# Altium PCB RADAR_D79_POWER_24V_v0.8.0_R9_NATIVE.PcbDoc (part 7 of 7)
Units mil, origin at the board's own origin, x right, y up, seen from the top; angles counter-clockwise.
Board outline 3110.24 x 3110.24 mil, 8 copper layers (Top Layer, GND1, SIG1, PWR1, PWR2, SIG2, GND2, Bottom Layer), stack 55.2 mil thick; 304 components, 269 nets, 1408 pads, 1366 vias.

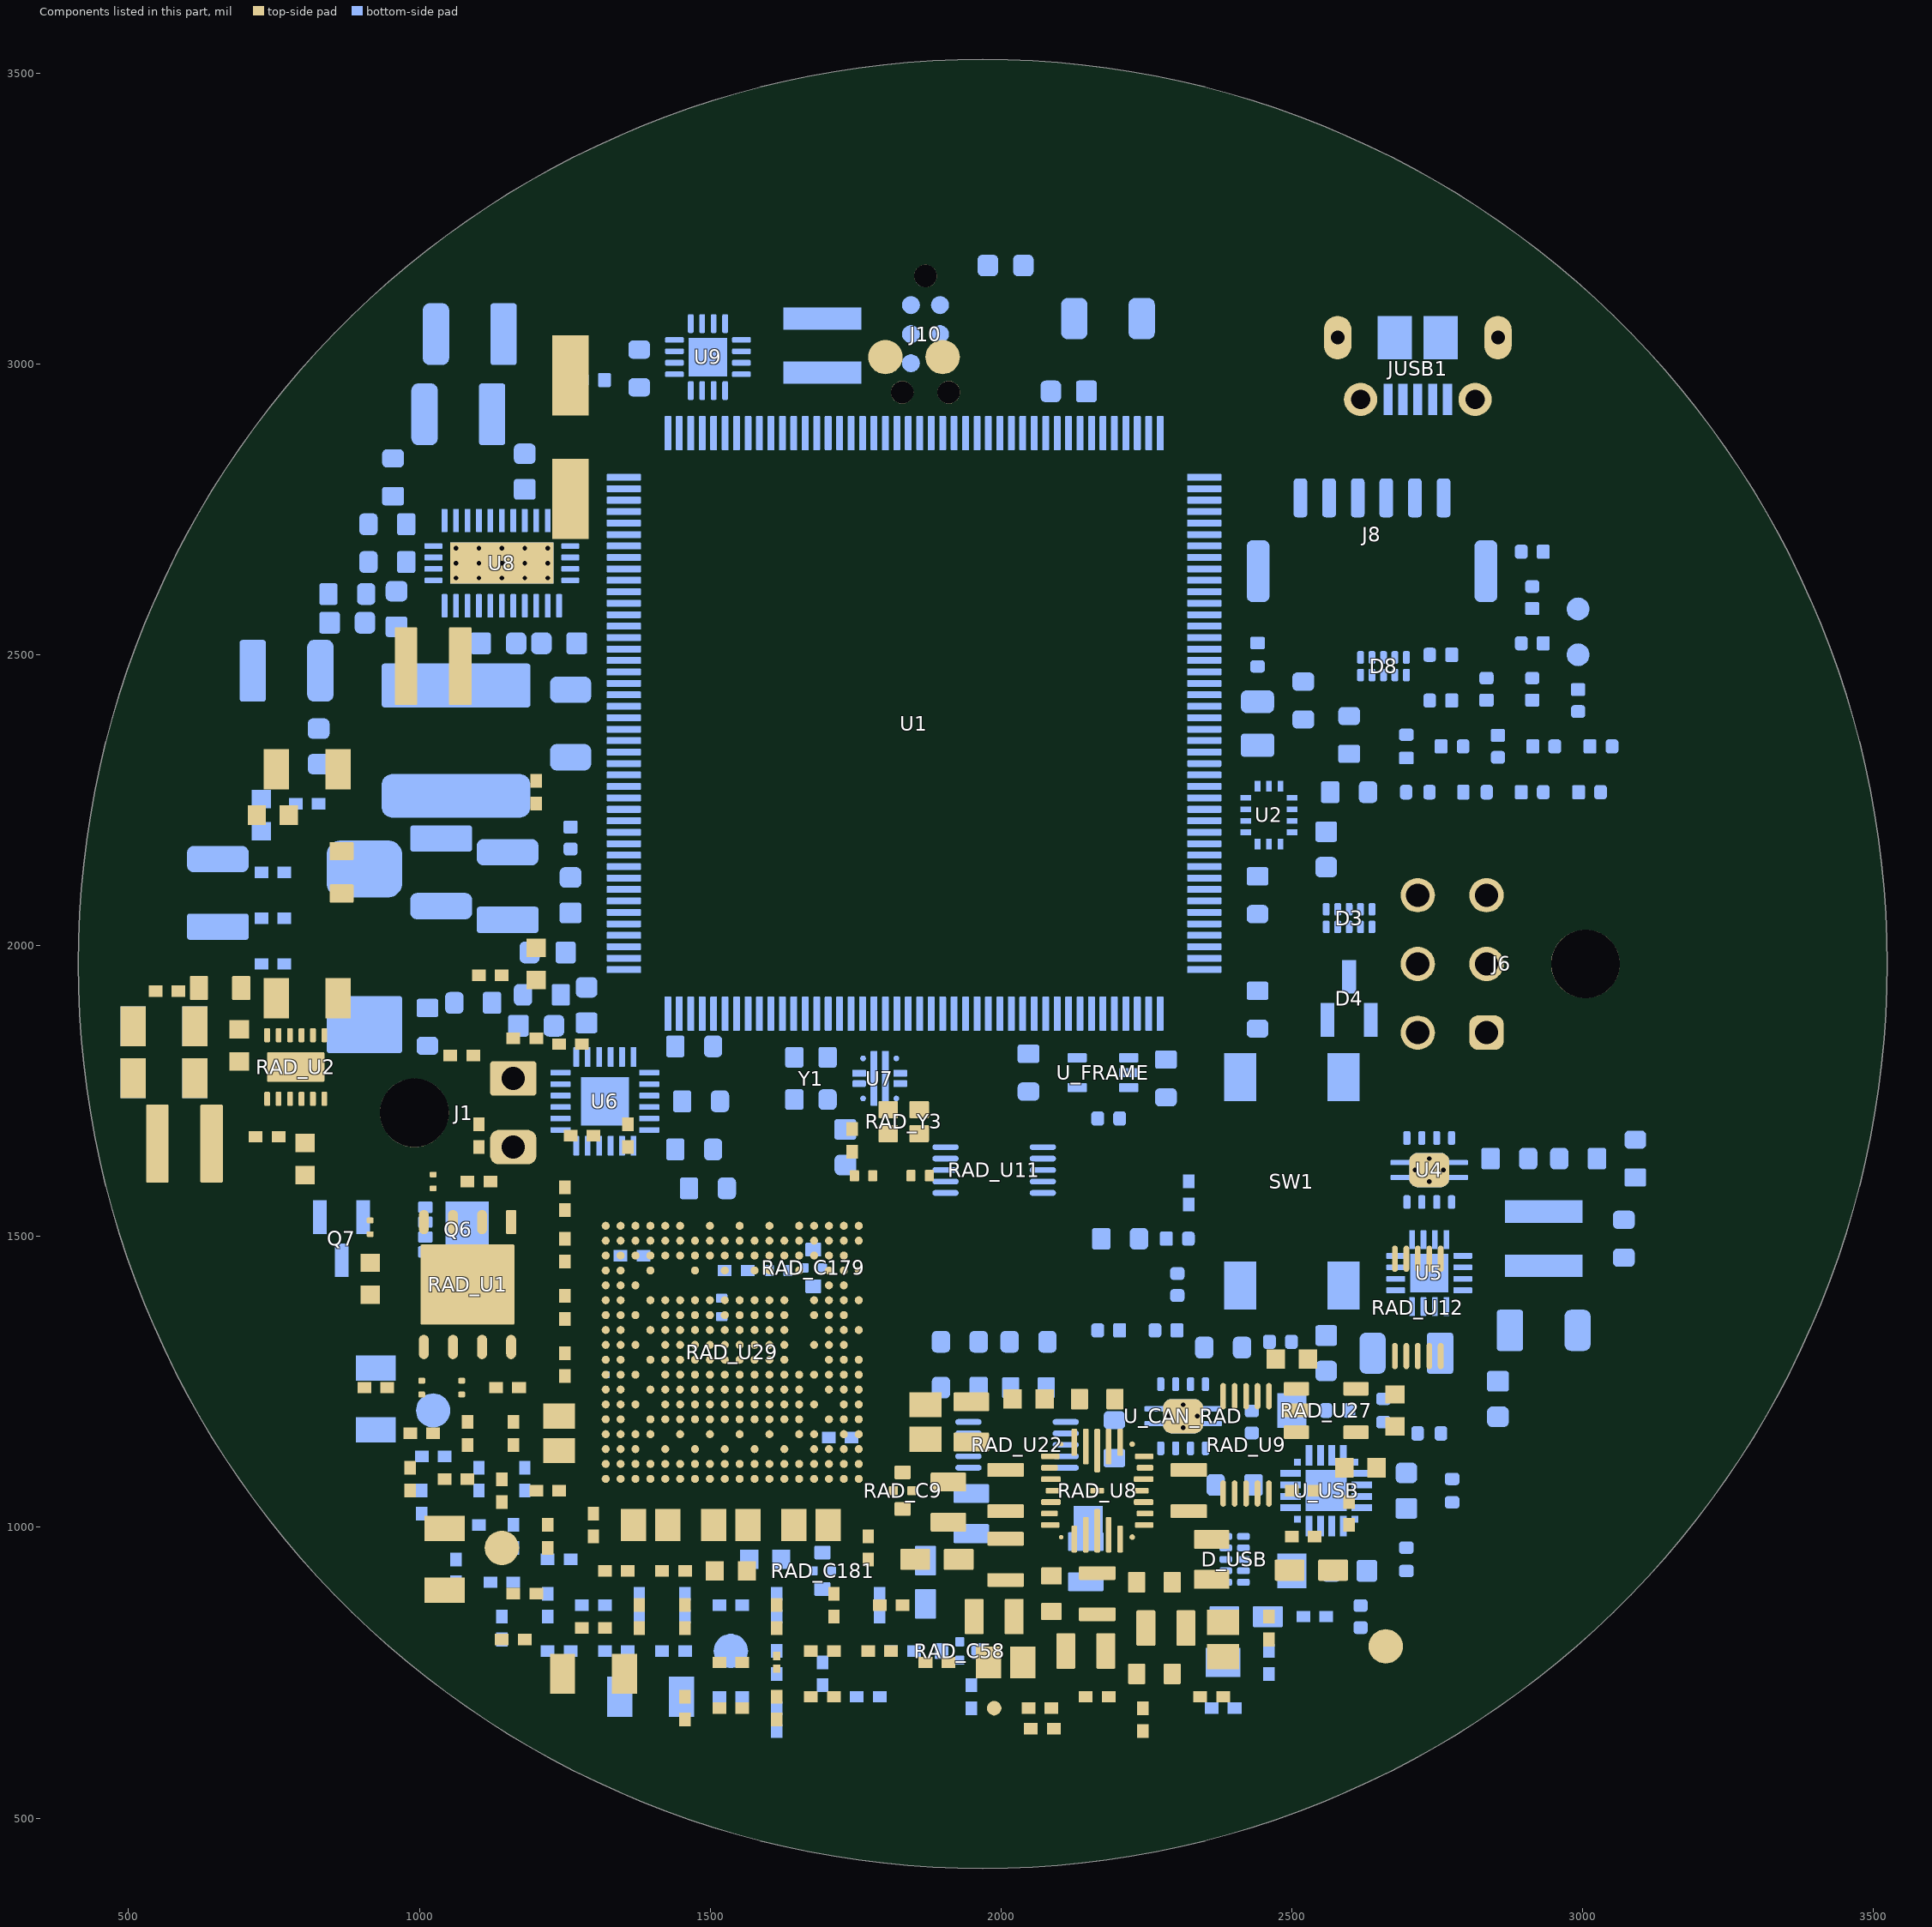
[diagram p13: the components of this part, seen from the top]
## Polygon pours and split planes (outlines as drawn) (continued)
GND on Bottom Layer "GND_BOTTOM_RETURN" (solid, remove dead copper, pour order 5): 3474.41,1968.5 3472.98,2034.19 3468.68,2099.75 3461.53,2165.06 3451.53,2230 3438.71,2294.44 3423.1,2358.26 3404.71,2421.34 3383.59,2483.55 3359.78,2544.79 3333.32,2604.93 3304.26,2663.85 3272.66,2721.46 3238.57,2777.63 3202.07,2832.26 3163.22,2885.24 3122.09,2936.48 3078.77,2985.88 3033.34,3033.34 2985.88,3078.77 2936.48,3122.09 2885.24,3163.22 2832.26,3202.07 2777.63,3238.57 2721.46,3272.66 2663.85,3304.26 2604.93,3333.32 2544.79,3359.78 2483.55,3383.59 2421.34,3404.71 2358.26,3423.1 2294.44,3438.71 2230,3451.53 2165.06,3461.53 2099.75,3468.68 2034.19,3472.98 1968.5,3474.41 1902.82,3472.98 1837.26,3468.68 1771.94,3461.53 1707.01,3451.53 1642.57,3438.71 1578.75,3423.1 1515.67,3404.71 1453.45,3383.59 1392.22,3359.78 1332.08,3333.32 1273.15,3304.26 1215.55,3272.66 1159.38,3238.57 1104.75,3202.07 1051.77,3163.22 1000.53,3122.09 951.13,3078.77 903.67,3033.34 858.23,2985.88 814.91,2936.48 773.79,2885.24 734.94,2832.26 698.44,2777.63 664.35,2721.46 632.75,2663.85 603.69,2604.93 577.23,2544.79 553.42,2483.55 532.3,2421.34 513.91,2358.26 498.29,2294.44 485.48,2230 475.48,2165.06 468.33,2099.75 464.03,2034.19 462.6,1968.5 464.03,1902.82 468.33,1837.26 475.48,1771.94 485.48,1707.01 498.29,1642.57 513.91,1578.75 532.3,1515.67 553.42,1453.45 577.23,1392.22 603.69,1332.08 632.75,1273.15 664.35,1215.55 698.44,1159.38 734.94,1104.75 773.79,1051.77 814.91,1000.53 858.23,951.13 903.67,903.67 951.13,858.23 1000.53,814.91 1051.77,773.79 1104.75,734.94 1159.38,698.44 1215.55,664.35 1273.15,632.75 1332.08,603.69 1392.22,577.23 1453.45,553.42 1515.67,532.3 1578.75,513.91 1642.57,498.29 1707.01,485.48 1771.94,475.48 1837.26,468.33 1902.82,464.03 1968.5,462.6 2034.19,464.03 2099.75,468.33 2165.06,475.48 2230,485.48 2294.44,498.29 2358.26,513.91 2421.34,532.3 2483.55,553.42 2544.79,577.23 2604.93,603.69 2663.85,632.75 2721.46,664.35 2777.63,698.44 2832.26,734.94 2885.24,773.79 2936.48,814.91 2985.88,858.23 3033.34,903.67 3078.77,951.13 3122.09,1000.53 3163.22,1051.77 3202.07,1104.75 3238.57,1159.38 3272.66,1215.55 3304.26,1273.15 3333.32,1332.08 3359.78,1392.22 3383.59,1453.45 3404.71,1515.67 3423.1,1578.75 3438.71,1642.57 3451.53,1707.01 3461.53,1771.94 3468.68,1837.26 3472.98,1902.82
TI_REGOUT_3V3 on PWR2 "REGOUT_3V3_WINDOW_8" (solid, pour order 8): 1479.33,1128.16 1484.49,1125.52 1489.88,1123.39 1495.45,1121.81 1501.16,1120.77 1506.93,1120.31 1512.73,1120.41 1518.48,1121.07 1524.15,1122.3 1529.66,1124.08 1534.98,1126.39 1540.04,1129.21 1544.81,1132.51 1549.22,1136.26 1553.25,1140.43 1556.85,1144.97 1559.99,1149.84 1562.63,1155 1564.75,1160.39 1566.34,1165.97 1567.37,1171.67 1567.84,1177.44 1567.74,1183.24 1567.08,1189 1565.85,1194.66 1564.07,1200.18 1561.76,1205.49 1558.94,1210.56 1555.64,1215.32 1551.89,1219.73 1547.72,1223.76 1543.18,1227.36 1538.31,1230.5 592.48,1775.58 587.32,1778.22 581.93,1780.35 576.36,1781.93 570.65,1782.97 564.88,1783.43 559.08,1783.34 553.33,1782.67 547.66,1781.44 542.15,1779.66 536.83,1777.35 531.77,1774.53 527,1771.23 522.59,1767.48 518.56,1763.31 514.96,1758.77 511.83,1753.9 509.18,1748.74 507.06,1743.35 505.47,1737.77 504.44,1732.07 503.97,1726.3 504.07,1720.5 504.73,1714.74 505.96,1709.08 507.74,1703.56 510.05,1698.25 512.87,1693.18 516.17,1688.42 519.92,1684.01 524.09,1679.98 528.63,1676.38 533.5,1673.24
TI_REGOUT_3V3 on PWR2 "REGOUT_3V3_WINDOW_9" (solid, pour order 9): 1746.1,974.42 1751.26,971.78 1756.65,969.65 1762.23,968.07 1767.93,967.03 1773.7,966.57 1779.5,966.66 1785.26,967.33 1790.92,968.56 1796.44,970.34 1801.75,972.65 1806.82,975.47 1811.58,978.77 1815.99,982.52 1820.02,986.69 1823.62,991.23 1826.76,996.1 1829.4,1001.26 1831.53,1006.65 1833.11,1012.23 1834.15,1017.93 1834.62,1023.7 1834.52,1029.5 1833.85,1035.26 1832.62,1040.92 1830.84,1046.44 1828.53,1051.75 1825.72,1056.82 1822.41,1061.58 1818.66,1065.99 1814.49,1070.02 1809.95,1073.62 1805.08,1076.76 1678.97,1149.43 1673.81,1152.08 1668.42,1154.2 1662.85,1155.79 1657.14,1156.82 1651.37,1157.29 1645.57,1157.19 1639.81,1156.53 1634.15,1155.3 1628.63,1153.52 1623.32,1151.21 1618.26,1148.39 1613.49,1145.09 1609.08,1141.34 1605.05,1137.17 1601.45,1132.63 1598.31,1127.76 1595.67,1122.6 1593.54,1117.21 1591.96,1111.63 1590.92,1105.93 1590.46,1100.15 1590.55,1094.36 1591.22,1088.6 1592.45,1082.94 1594.23,1077.42 1596.54,1072.11 1599.36,1067.04 1602.66,1062.28 1606.41,1057.86 1610.58,1053.84 1615.12,1050.24 1619.99,1047.1
TI_REGOUT_3V3 on PWR2 "REGOUT_3V3_WINDOW_10" (solid, pour order 10): 1580.31,1178.91 1582.2,1178.48 1584.12,1178.24 1586.05,1178.19 1587.97,1178.34 1589.88,1178.66 1591.74,1179.18 1593.54,1179.87 1595.27,1180.74 1596.9,1181.77 1598.42,1182.96 1599.83,1184.29 1601.09,1185.75 1602.2,1187.33 1603.15,1189.01 1603.94,1190.78 1604.55,1192.61 1604.97,1194.49 1605.21,1196.41 1605.26,1198.34 1605.12,1200.27 1604.79,1202.17 1604.27,1204.03 1603.58,1205.84 1602.71,1207.56 1601.68,1209.2 1600.49,1210.72 1599.16,1212.12 1597.7,1213.38 1596.12,1214.5 1594.44,1215.45 1592.68,1216.23 1590.84,1216.84 1380.7,1275.17 1378.81,1275.59 1376.9,1275.83 1374.96,1275.88 1373.04,1275.74 1371.13,1275.41 1369.27,1274.9 1367.47,1274.2 1365.74,1273.34 1364.11,1272.3 1362.59,1271.12 1361.19,1269.79 1359.92,1268.32 1358.81,1266.74 1357.86,1265.06 1357.07,1263.3 1356.47,1261.47 1356.04,1259.58 1355.8,1257.66 1355.75,1255.73 1355.89,1253.81 1356.22,1251.9 1356.74,1250.04 1357.43,1248.24 1358.3,1246.51 1359.33,1244.88 1360.52,1243.35 1361.85,1241.95 1363.31,1240.69 1364.89,1239.58 1366.57,1238.62 1368.33,1237.84 1370.17,1237.23
TI_REGOUT_3V3 on PWR2 "REGOUT_3V3_WINDOW_11" (solid, pour order 11): 1619.9,1154.71 1621.61,1153.81 1623.4,1153.08 1625.25,1152.53 1627.15,1152.16 1629.07,1151.99 1631,1152 1632.93,1152.2 1634.82,1152.59 1636.66,1153.16 1638.44,1153.91 1640.14,1154.83 1641.74,1155.91 1643.23,1157.15 1644.59,1158.52 1645.8,1160.02 1646.87,1161.63 1647.77,1163.34 1648.49,1165.13 1649.04,1166.98 1649.41,1168.88 1649.59,1170.8 1649.58,1172.74 1649.38,1174.66 1648.99,1176.55 1648.42,1178.4 1647.67,1180.18 1646.75,1181.87 1645.66,1183.47 1644.43,1184.96 1643.05,1186.32 1641.55,1187.53 1639.94,1188.6 1595.6,1214.82 1593.89,1215.72 1592.1,1216.45 1590.25,1217 1588.35,1217.36 1586.43,1217.54 1584.5,1217.53 1582.57,1217.33 1580.68,1216.94 1578.84,1216.37 1577.06,1215.62 1575.36,1214.7 1573.76,1213.61 1572.27,1212.38 1570.91,1211.01 1569.7,1209.51 1568.63,1207.89 1567.73,1206.18 1567.01,1204.39 1566.46,1202.54 1566.09,1200.65 1565.91,1198.72 1565.92,1196.79 1566.12,1194.87 1566.51,1192.98 1567.08,1191.13 1567.83,1189.35 1568.75,1187.65 1569.84,1186.05 1571.07,1184.57 1572.45,1183.21 1573.95,1181.99 1575.56,1180.93
TI_REGOUT_3V3 on PWR2 "REGOUT_3V3_WINDOW_12" (solid, pour order 12): 1761.65,1011.69 1763.08,1010.39 1764.63,1009.24 1766.29,1008.24 1768.03,1007.41 1769.85,1006.76 1771.72,1006.29 1773.63,1006 1775.56,1005.91 1777.49,1006 1779.4,1006.28 1781.28,1006.75 1783.1,1007.39 1784.85,1008.22 1786.5,1009.21 1788.06,1010.36 1789.49,1011.65 1790.79,1013.08 1791.94,1014.63 1792.94,1016.29 1793.77,1018.03 1794.42,1019.85 1794.89,1021.72 1795.18,1023.63 1795.28,1025.56 1795.18,1027.49 1794.9,1029.4 1794.44,1031.28 1793.79,1033.1 1792.96,1034.85 1791.97,1036.5 1790.82,1038.06 1789.53,1039.49 1643.86,1185.55 1642.43,1186.85 1640.88,1188.01 1639.22,1189 1637.48,1189.83 1635.66,1190.48 1633.79,1190.96 1631.88,1191.24 1629.95,1191.34 1628.02,1191.25 1626.11,1190.97 1624.23,1190.5 1622.41,1189.85 1620.67,1189.03 1619.01,1188.04 1617.45,1186.89 1616.02,1185.59 1614.72,1184.16 1613.57,1182.61 1612.57,1180.96 1611.74,1179.21 1611.09,1177.39 1610.62,1175.52 1610.33,1173.61 1610.24,1171.68 1610.33,1169.75 1610.61,1167.84 1611.08,1165.96 1611.72,1164.14 1612.55,1162.4 1613.54,1160.74 1614.69,1159.19 1615.98,1157.75
TI_REGOUT_3V3 on PWR2 "REGOUT_3V3_WINDOW_13" (solid, pour order 13): 1513.98,1087.64 1517.05,1085.29 1520.33,1083.26 1523.8,1081.56 1527.42,1080.2 1531.15,1079.21 1534.97,1078.59 1538.82,1078.35 1542.68,1078.48 1546.51,1078.99 1550.27,1079.88 1553.93,1081.13 1557.45,1082.73 1560.79,1084.67 1563.92,1086.93 1566.82,1089.48 1569.46,1092.31 1571.8,1095.38 1573.84,1098.66 1575.54,1102.13 1576.89,1105.75 1577.88,1109.49 1578.5,1113.3 1578.75,1117.15 1578.61,1121.02 1578.1,1124.85 1577.22,1128.61 1575.97,1132.26 1574.36,1135.78 1572.42,1139.12 1570.17,1142.25 1567.61,1145.15 1564.79,1147.79 1400.84,1286.28 1397.77,1288.62 1394.48,1290.66 1391.01,1292.36 1387.39,1293.71 1383.66,1294.7 1379.85,1295.32 1375.99,1295.57 1372.13,1295.43 1368.3,1294.92 1364.54,1294.03 1360.88,1292.78 1357.37,1291.18 1354.03,1289.24 1350.89,1286.99 1347.99,1284.43 1345.36,1281.61 1343.01,1278.54 1340.98,1275.25 1339.28,1271.78 1337.92,1268.16 1336.93,1264.43 1336.31,1260.62 1336.07,1256.76 1336.2,1252.9 1336.71,1249.07 1337.6,1245.31 1338.85,1241.65 1340.45,1238.14 1342.39,1234.79 1344.65,1231.66 1347.2,1228.76 1350.03,1226.12
TI_REGOUT_3V3 on PWR2 "REGOUT_3V3_WINDOW_14" (solid, pour order 14): 1565.21,1058.46 1568.68,1056.76 1572.3,1055.4 1576.03,1054.41 1579.84,1053.79 1583.7,1053.55 1587.56,1053.68 1591.39,1054.2 1595.15,1055.08 1598.81,1056.33 1602.32,1057.93 1605.66,1059.87 1608.8,1062.13 1611.7,1064.69 1614.33,1067.51 1616.68,1070.58 1618.71,1073.87 1620.41,1077.34 1621.76,1080.96 1622.75,1084.69 1623.37,1088.5 1623.62,1092.36 1623.48,1096.22 1622.97,1100.05 1622.08,1103.81 1620.83,1107.47 1619.23,1110.98 1617.29,1114.32 1615.03,1117.46 1612.48,1120.36 1609.65,1122.99 1606.58,1125.34 1603.3,1127.37 1558.43,1152.17 1554.96,1153.87 1551.34,1155.22 1547.6,1156.21 1543.79,1156.84 1539.93,1157.08 1536.07,1156.94 1532.24,1156.43 1528.48,1155.54 1524.83,1154.29 1521.31,1152.69 1517.97,1150.75 1514.84,1148.49 1511.94,1145.94 1509.3,1143.11 1506.96,1140.04 1504.92,1136.76 1503.22,1133.29 1501.87,1129.67 1500.88,1125.93 1500.26,1122.12 1500.02,1118.27 1500.15,1114.4 1500.66,1110.57 1501.55,1106.81 1502.8,1103.16 1504.4,1099.64 1506.34,1096.3 1508.6,1093.17 1511.15,1090.27 1513.98,1087.63 1517.05,1085.29 1520.34,1083.26
TI_REGOUT_3V3 on PWR2 "REGOUT_3V3_WINDOW_15" (solid, pour order 15): 1681.59,1048.86 1685.46,1048.87 1689.3,1049.25 1693.09,1050.01 1696.78,1051.14 1700.35,1052.62 1703.76,1054.45 1706.96,1056.6 1709.95,1059.06 1712.68,1061.79 1715.12,1064.78 1717.26,1068 1719.08,1071.41 1720.55,1074.98 1721.67,1078.68 1722.42,1082.47 1722.79,1086.32 1722.78,1090.18 1722.4,1094.02 1721.64,1097.81 1720.51,1101.51 1719.03,1105.08 1717.2,1108.48 1715.05,1111.69 1712.6,1114.67 1709.86,1117.4 1706.87,1119.85 1703.65,1121.99 1700.24,1123.8 1696.67,1125.28 1692.97,1126.39 1689.18,1127.14 1685.34,1127.51 1586.12,1132.24 1582.26,1132.23 1578.42,1131.85 1574.63,1131.09 1570.93,1129.96 1567.37,1128.48 1563.96,1126.65 1560.75,1124.5 1557.77,1122.04 1555.04,1119.31 1552.59,1116.32 1550.45,1113.1 1548.64,1109.69 1547.16,1106.12 1546.05,1102.42 1545.3,1098.63 1544.93,1094.79 1544.93,1090.92 1545.32,1087.08 1546.08,1083.29 1547.2,1079.59 1548.69,1076.03 1550.51,1072.62 1552.66,1069.41 1555.12,1066.43 1557.86,1063.7 1560.85,1061.26 1564.06,1059.11 1567.47,1057.3 1571.04,1055.82 1574.74,1054.71 1578.53,1053.96 1582.38,1053.59
TI_REGOUT_3V3 on PWR2 "REGOUT_3V3_WINDOW_16" (solid, pour order 16): 1753.46,993.03 1756.76,991.01 1760.24,989.34 1763.87,988.01 1767.61,987.04 1771.43,986.44 1775.28,986.22 1779.14,986.38 1782.97,986.92 1786.73,987.83 1790.37,989.1 1793.88,990.73 1797.21,992.69 1800.33,994.96 1803.21,997.54 1805.83,1000.38 1808.15,1003.46 1810.17,1006.76 1811.85,1010.24 1813.18,1013.87 1814.14,1017.61 1814.74,1021.43 1814.96,1025.28 1814.8,1029.14 1814.26,1032.97 1813.35,1036.73 1812.08,1040.37 1810.46,1043.88 1808.49,1047.21 1806.22,1050.33 1803.65,1053.21 1800.8,1055.83 1797.72,1058.15 1705.59,1120.75 1702.29,1122.76 1698.81,1124.44 1695.19,1125.77 1691.45,1126.74 1687.63,1127.34 1683.77,1127.56 1679.91,1127.4 1676.08,1126.86 1672.33,1125.95 1668.68,1124.68 1665.18,1123.05 1661.85,1121.09 1658.73,1118.82 1655.84,1116.24 1653.23,1113.4 1650.9,1110.32 1648.89,1107.02 1647.21,1103.54 1645.88,1099.91 1644.91,1096.17 1644.32,1092.35 1644.1,1088.5 1644.26,1084.63 1644.79,1080.81 1645.7,1077.05 1646.98,1073.41 1648.6,1069.9 1650.56,1066.57 1652.84,1063.45 1655.41,1060.57 1658.25,1057.95 1661.34,1055.63

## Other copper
Top Layer:
  rectangle net TI_RX1: 1411.84,1961.62 1464.99,2004.14
  rectangle net TI_RX1: 1417.74,2021.76 1459.08,2064.28
  rectangle net TI_RX1: 1422.27,2081.9 1454.56,2124.42
  rectangle net TI_RX1: 1425.62,2142.04 1451.21,2184.56
  rectangle net TI_RX1: 1425.62,2202.18 1451.21,2244.7
  rectangle net TI_RX1: 1422.27,2262.33 1454.56,2304.85
  rectangle net TI_RX1: 1417.74,2322.47 1459.08,2364.99
  rectangle net TI_RX1: 1411.84,2382.61 1464.99,2425.13
  rectangle net TI_RX2: 1486.64,1961.62 1539.79,2004.14
  rectangle net TI_RX2: 1492.55,2021.76 1533.89,2064.28
  rectangle net TI_RX2: 1497.08,2081.9 1529.36,2124.42
  rectangle net TI_RX2: 1500.42,2142.04 1526.01,2184.56
  rectangle net TI_RX2: 1500.42,2202.18 1526.01,2244.7
  rectangle net TI_RX2: 1497.08,2262.33 1529.36,2304.85
  rectangle net TI_RX2: 1492.55,2322.47 1533.89,2364.99
  rectangle net TI_RX2: 1486.64,2382.61 1539.79,2425.13
  rectangle net TI_RX3: 1561.45,1961.62 1614.59,2004.14
  rectangle net TI_RX3: 1567.35,2021.76 1608.69,2064.28
  rectangle net TI_RX3: 1571.88,2081.9 1604.16,2124.42
  rectangle net TI_RX3: 1575.22,2142.04 1600.82,2184.56
  rectangle net TI_RX3: 1575.22,2202.18 1600.82,2244.7
  rectangle net TI_RX3: 1571.88,2262.33 1604.16,2304.85
  rectangle net TI_RX3: 1567.35,2322.47 1608.69,2364.99
  rectangle net TI_RX3: 1561.45,2382.61 1614.59,2425.13
  rectangle net TI_RX4: 1636.25,1961.62 1689.4,2004.14
  rectangle net TI_RX4: 1642.15,2021.76 1683.49,2064.28
  rectangle net TI_RX4: 1646.68,2081.9 1678.96,2124.42
  rectangle net TI_RX4: 1650.03,2142.04 1675.62,2184.56
  rectangle net TI_RX4: 1650.03,2202.18 1675.62,2244.7
  rectangle net TI_RX4: 1646.68,2262.33 1678.96,2304.85
  rectangle net TI_RX4: 1642.15,2322.47 1683.49,2364.99
  rectangle net TI_RX4: 1636.25,2382.61 1689.4,2425.13
  rectangle net TI_TX1: 1903.16,1968.57 1956.31,2011.08
  rectangle net TI_TX1: 1909.07,2028.71 1950.41,2071.23
  rectangle net TI_TX1: 1913.6,2088.85 1945.88,2131.37
  rectangle net TI_TX1: 1916.94,2148.99 1942.53,2191.51
  rectangle net TI_TX1: 1916.94,2209.13 1942.53,2251.65
  rectangle net TI_TX1: 1913.6,2269.27 1945.88,2311.79
  rectangle net TI_TX1: 1909.07,2329.42 1950.41,2371.94
  rectangle net TI_TX1: 1903.16,2389.56 1956.31,2432.08
  rectangle net TI_TX2: 2057.41,2091.99 2110.56,2134.51
  rectangle net TI_TX2: 2063.32,2152.13 2104.66,2194.65
  rectangle net TI_TX2: 2067.85,2212.27 2100.13,2254.79
  rectangle net TI_TX2: 2071.19,2272.42 2096.79,2314.94
  rectangle net TI_TX2: 2071.19,2332.56 2096.79,2375.08
  rectangle net TI_TX2: 2067.85,2392.7 2100.13,2435.22
  rectangle net TI_TX2: 2063.32,2452.84 2104.66,2495.36
  rectangle net TI_TX2: 2057.41,2512.98 2110.56,2555.5
  rectangle net TI_TX3: 2211.71,1968.57 2264.86,2011.08
  rectangle net TI_TX3: 2217.61,2028.71 2258.95,2071.23
  rectangle net TI_TX3: 2222.14,2088.85 2254.42,2131.37
  rectangle net TI_TX3: 2225.49,2148.99 2251.08,2191.51
  rectangle net TI_TX3: 2225.49,2209.13 2251.08,2251.65
  rectangle net TI_TX3: 2222.14,2269.27 2254.42,2311.79
  rectangle net TI_TX3: 2217.61,2329.42 2258.95,2371.94
  rectangle net TI_TX3: 2211.71,2389.56 2264.86,2432.08
  rectangle net TI_TX4: 2520.25,1968.57 2573.4,2011.08
  rectangle net TI_TX4: 2526.16,2028.71 2567.49,2071.23
  rectangle net TI_TX4: 2530.68,2088.85 2562.97,2131.37
  rectangle net TI_TX4: 2534.03,2148.99 2559.62,2191.51
  rectangle net TI_TX4: 2534.03,2209.13 2559.62,2251.65
  rectangle net TI_TX4: 2530.68,2269.27 2562.97,2311.79
  rectangle net TI_TX4: 2526.16,2329.42 2567.49,2371.94
  rectangle net TI_TX4: 2520.25,2389.56 2573.4,2432.08

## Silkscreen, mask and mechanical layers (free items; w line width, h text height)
M1 Board Outline:
  circle w3.94: c1968.5,1968.5 r1555.12
M2 Board Dimensions:
  lines w6.3: 1332.75,1735.72 1409.87,1735.72 1409.87,1623.56 1451.09,1582.35 1451.09,1537.98 1454.62,1534.44 1465.76,1534.44 1465.76,1507.74 1478.4,1507.74 1481.94,1511.28 1481.94,1534.44 1516.89,1534.44 1516.89,1507.74 1529.63,1507.74 1533.16,1511.28 1533.16,1534.44 1568.07,1534.44 1568.07,1507.74 1584.35,1507.74 1584.35,1534.44 1619.34,1534.44 1619.34,1507.74 1635.67,1507.74 1635.67,1535.6 1685.26,1585.19 1685.26,1629.06 1700.22,1644.02 1700.22,1813.89 1850.79,1813.89 1938.06,1726.62 1938.06,1565.78 1874.58,1502.3 1847.63,1502.3 1842.57,1497.24 1771.99,1497.24 1771.99,1475.16 1746.18,1475.16 1746.18,1458.97 1771.99,1458.97 1771.99,1424.03 1746.18,1424.03 1746.18,1407.79 1771.99,1407.79 1771.99,1372.89 1746.18,1372.89 1746.18,1360.15 1749.72,1356.61 1771.99,1356.61 1771.99,1321.71 1746.18,1321.71 1746.18,1305.43 1771.99,1305.43 1771.99,1287.99 2635.41,1287.99 2635.41,2872.45 1332.75,2872.45 1332.75,1735.72
  text "RF WINDOW REF" at 1456.69,1732.28 h41.34
M3 3D STEP Top:
  lines w6.3: 1222.86,985.81 1852.78,985.81 1852.78,1615.74 1222.86,1615.74 1222.86,985.81 ; 2472.44,944.88 2755.91,944.88 2755.91,1181.1 2472.44,1181.1 2472.44,944.88
  text "REAR HEAT RESERVE" at 1259.84,1181.1 h41.34
  text "USB BRIDGE RESERVE" at 2322.83,1141.73 h41.34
